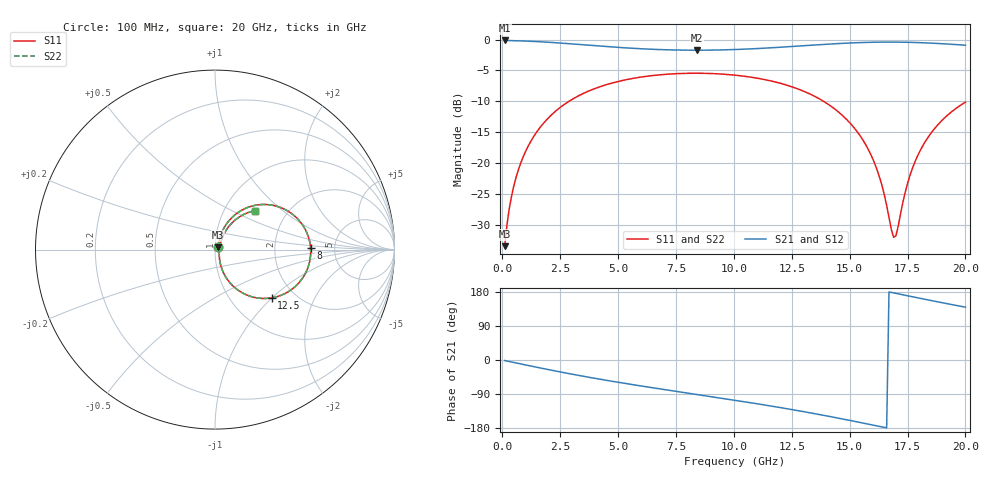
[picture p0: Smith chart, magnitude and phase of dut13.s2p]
! Touchstone file exported from HFSS 2026.1.0
!  File:  C:/ffzhzh/LocalFiles/Ansys_Project_Files/temp_test_TSV_RDL_13_1782980186_45568.aedt
!  Generated:  04:26:24 PM Jul  2, 2026
!  Design:  TSV_RDL
!  Project:  temp_test_TSV_RDL_13_1782980186_45568
! Variables:
!  h_bsmrdl = 5.23um
!  h_ox = 20um
!  h_rdl = 5um
!  h_sub = 79.8um
!  h_tmrdl = 3.73um
!  h_tsv = 79.8um
!  h_via = 3um
!  l_bsmrdl = 327.27um
!  l_sub = 3628.48um
!  l_tmrdl = 532.2um
!  m_sub = 200um
!  pitch = 47.34um
!  r_tsv = 4.69um
!  s_tmrdl = 10um
!  w_bsmrdl = 12.66um
!  w_sub = 500um
!  w_tmrdl = 26.63um
!  x_tsv_center1 = 545.515um
!  x_tsv_center2 = 885.445um
!  x_tsv_center3 = 1444.275um
!  x_tsv_center4 = 1784.205um
!  x_tsv_center5 = 2343.035um
!  x_tsv_center6 = 2682.965um
# GHz S MA R 50.000000
! Terminal data exported
! Port[1] = TM_RDL1_1_T1
! Port[2] = TM_RDL5_1_T1
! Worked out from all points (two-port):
!   200 points, 100 MHz to 20 GHz, reference 50 ohm
!   highest |S21| = -0.15 dB at 100 MHz (marker M1); lowest = -1.7 dB at 8.4 GHz (marker M2)
!   |S21| within 3 dB of the highest: start of sweep to end of sweep
!   lowest |S11| = -33.5 dB at 100 MHz (marker M3), VSWR 1.04, Z = 51.7 + j1.34 ohm
!   |S11| at or under -10 dB: start of sweep to 2.883 GHz; 13.87 GHz to end of sweep
!   |S22| runs from -33.5 to -5.5 dB; largest |S21 - S12| = 6.3e-14
!   S11 on the Smith chart (normalised r, x): 100 MHz: 1.03, +0.03; 8 GHz: 3.28, +0.07; 12.5 GHz: 1.53, -1.00; 20 GHz: 1.39, +0.67
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0.1  0.02118 37.6  0.9834 -1.4  0.9834 -1.4  0.02118 37.6
! Gamma 0 0 0 0
! Port Impedance 50 0 50 0
0.3  0.04245 61.1  0.9814 -4.0  0.9814 -4.0  0.04245 61.1
0.5  0.0654 66.7  0.9792 -6.6  0.9792 -6.6  0.0654 66.7
1.1  0.1348 67.2  0.9709 -14.3  0.9709 -14.3  0.1348 67.2
2.1  0.2429 58.2  0.9485 -26.7  0.9485 -26.7  0.2429 58.2
3.5  0.366 43.4  0.9068 -42.9  0.9068 -42.9  0.366 43.4
6.8  0.5178 11.5  0.8296 -76.2  0.8296 -76.2  0.5178 11.5
8  0.5328 0.8  0.8203 -87.3  0.8203 -87.3  0.5328 0.8
8.4  0.5335 -2.7  0.8197 -90.9  0.8197 -90.9  0.5335 -2.7
10.1  0.5135 -17.9  0.8309 -106.7  0.8309 -106.7  0.5135 -17.9
12.5  0.4147 -40.4  0.8784 -130.7  0.8784 -130.7  0.4147 -40.4
13.4  0.3537 -49.4  0.9012 -140.6  0.9012 -140.6  0.3536 -49.4
14.7  0.2418 -62.2  0.9319 -155.7  0.9319 -155.7  0.2418 -62.2
15.6  0.1507 -69.4  0.947 -166.6  0.947 -166.6  0.1506 -69.3
16.2  0.08649 -69.5  0.9527 -174.1  0.9527 -174.1  0.08644 -69.5
16.7  0.03631 -49.4  0.9543 179.6  0.9543 179.6  0.03627 -49.4
16.9  0.02497 -13.9  0.9541 177.0  0.9541 177.0  0.02497 -13.8
17  0.0257 10.6  0.9538 175.8  0.9538 175.8  0.02573 10.7
17.5  0.06812 56.8  0.9506 169.5  0.9506 169.5  0.06818 56.8
18.1  0.1315 59.9  0.943 162.0  0.943 162.0  0.1316 59.9
18.9  0.2128 54.6  0.9277 152.3  0.9277 152.3  0.2128 54.6
20  0.3109 44.2  0.9004 139.4  0.9004 139.4  0.311 44.2
